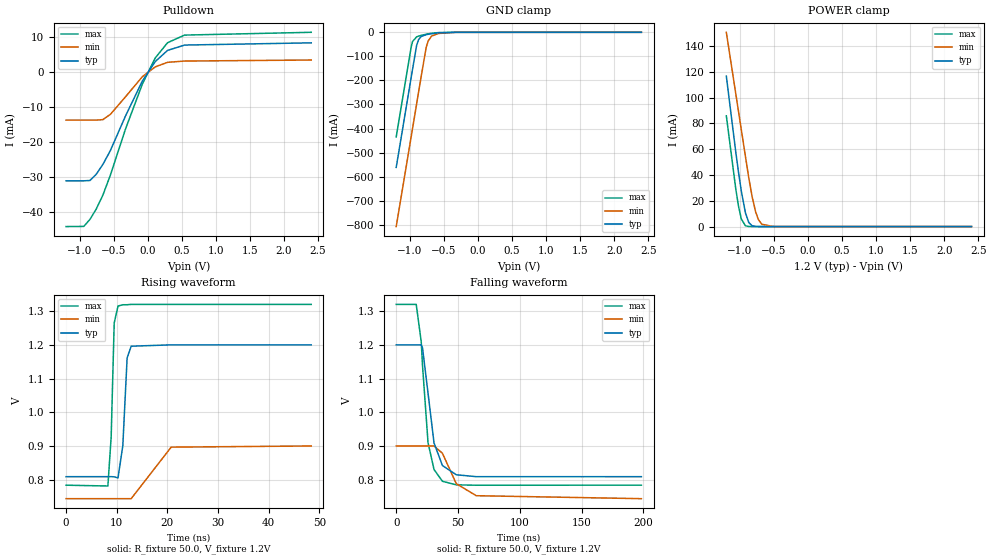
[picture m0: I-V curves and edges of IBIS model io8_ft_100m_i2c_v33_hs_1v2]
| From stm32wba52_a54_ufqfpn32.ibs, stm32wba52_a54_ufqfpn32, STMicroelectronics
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[Model]   io8_ft_100m_i2c_v33_hs_1v2
Model_type I/O_open_drain
Polarity   Non-Inverting
Enable   Active-Low
| CAP_THRESHOLD on pad IOFT is "UDTCAPC" :
| Rising=30.0% of vddiom   Falling=70.0% of vddiom
| C_comp min and max val. don't necessarily correlate with the min and max pvt
| but are the smallest and greatest pad capacitance found.
| var   typ   min   max
C_comp   1.75955pF  1.58205pF  1.89750pF
|C_comp_pulldown   1.75955pF  1.58205pF  1.89750pF
Vinl = 450.0mV
Vinh = 660.0mV
Vmeas = 600.0mV   | Reference voltage for timing measurements
Cref  = 50.0pF   | Timing specification test load capacitance value
Rref  = 1.0MOhm   | Timing specification test load resistance value
Vref  = 660.0mV   | Timing specification test load voltage
[Model Spec]
| TIME_THRESHOLD on pin ZII2CV11 is "CMOS" :
| Rising=50.0% of vdd   Falling=50.0% of vdd
Vinl 436.50000mV 342.50000mV 466.50000mV
Vinh 753.50000mV 549.50000mV 839.50000mV
| variable   typ   min   max
[Temperature Range] 25.0 140.0 -40.0
| variable   typ   min   max
[Voltage Range] 1.2V 900.0mV 1.32V
| variable   typ   min   max
[POWER Clamp Reference] 1.2V 900.0mV 1.32V
| variable   typ   min   max
[GND Clamp Reference] 0V 0V 0V
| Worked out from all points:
|   slope of the pulldown table from 0 to 0.18 V, typ, clamps not added: 40.6 ohm
|   GND clamp passes 1 mA (typ) near -0.51 V on its own axis
|   POWER clamp passes 1 mA (typ) near -0.83 V on its own axis
|   rising waveform, R_fixture 50.0, V_fixture 1.2V: 20-80 % time 747ps typ, 1.42ns min, 564ps max; typ from 0.809 V to 1.2 V
|   falling waveform, R_fixture 50.0, V_fixture 1.2V: 20-80 % time 8.05ns typ, 13.6ns min, 6.4ns max; typ from 1.2 V to 0.809 V
[POWER Clamp]
-1.2V     116.7mA    150.7mA    85.92mA
-1.06V    57.23mA    102.6mA    28.68mA
-1.02V    41.75mA    88.91mA    15.5mA
-980mV    27.6mA     75.18mA    5.935mA
-920mV    10.75mA    54.6mA     597.6uA
-870mV    3.065mA    37.68mA    60.82uA
-820mV    594.6uA    22.85mA    5.912uA
-770mV    99.71uA    11.47mA    572nA
-730mV    23.34uA    5.552mA    88.29nA
-680mV    3.779uA    1.833mA    8.565nA
-510mV    7.889nA    23.13uA    53.67pA
2.4V      0A         0A         0A
[GND Clamp]
-1.2V     -561.6mA   -807.5mA   -434.8mA
-980mV    -187.6mA   -433.5mA   -60.76mA
-960mV    -153.6mA   -399.5mA   -38.21mA
-900mV    -54.17mA   -297.5mA   -18.87mA
-870mV    -29.55mA   -246.5mA   -15.73mA
-830mV    -17.05mA   -178.5mA   -12.57mA
-760mV    -9.921mA   -62.77mA   -8.045mA
-730mV    -8.191mA   -35.56mA   -6.403mA
-680mV    -5.826mA   -15.57mA   -4.089mA
-580mV    -2.43mA    -5.043mA   -1.157mA
-330mV    -11.72uA   -245.5uA   -300.5nA
2.4V      872pA      1.056uA    338.3pA
| variable   typ   min   max
[Pullup Reference] 1.2V 900.0mV 1.32V
| variable   typ   min   max
[Pulldown Reference] 0V 0V 0V
[Pulldown]
-1.2V     -31.2mA    -13.81mA   -44.3mA
-940mV    -31.2mA    -13.81mA   -44.26mA
-850mV    -31.11mA   -13.81mA   -42.26mA
-760mV    -29.39mA   -13.81mA   -39.38mA
-660mV    -26.52mA   -13.68mA   -35.32mA
-550mV    -22.55mA   -12.17mA   -29.6mA
-330mV    -12.74mA   -7.204mA   -16.5mA
-80mV     -2.622mA   -1.37mA    -3.49mA
110mV     2.963mA    1.428mA    3.999mA
290mV     6.144mA    2.737mA    8.347mA
540mV     7.674mA    3.096mA    10.53mA
2.4V      8.312mA    3.39mA     11.33mA
[Ramp]
dV/dt_r 234.64969mV/734.00548ps 93.74534mV/1.39277ns 321.76568mV/559.54409ps
dV/dt_f 234.6588mV/7.92715ns 93.76894mV/13.216ns 321.7731mV/6.31518ns
R_load = 50.0
| Removed startup time: 0s 0s 0s  .
| Removed end time: 48.4ns.
[Rising Waveform]
R_fixture   = 50.0
V_fixture   = 1.2V
V_fixture_min = 900.0mV
V_fixture_max = 1.32V
0s        808.9mV    743.7mV    783.7mV
8.25ns    808.9mV    743.7mV    781.3mV
8.9ns     809mV      743.7mV    926.4mV
9.5ns     808.5mV    743.7mV    1.265V
10.25ns   805.2mV    743.7mV    1.315V
11.2ns    900.8mV    743.7mV    1.319V
12.05ns   1.161V     743.7mV    1.319V
12.85ns   1.196V     743.7mV    1.32V
20.75ns   1.2V       896.6mV    1.32V
48.4ns    1.2V       900mV      1.32V
| Removed startup time: 0s 0s 0s  .
| Removed end time: 198.4ns.
[Falling Waveform]
R_fixture   = 50.0
V_fixture   = 1.2V
V_fixture_min = 900.0mV
V_fixture_max = 1.32V
0s        1.2V       900mV      1.32V
16.2ns    1.2V       900mV      1.32V
20.25ns   1.2V       900mV      1.209V
21.25ns   1.192V     900mV      1.141V
25.75ns   1.057V     900mV      909.8mV
30.6ns    909.1mV    899.9mV    830.3mV
37.4ns    842mV      878.4mV    795.3mV
48.6ns    814.6mV    788.2mV    784.7mV
64.8ns    809mV      752.5mV    783.6mV
198.4ns   808.9mV    743.7mV    783.7mV
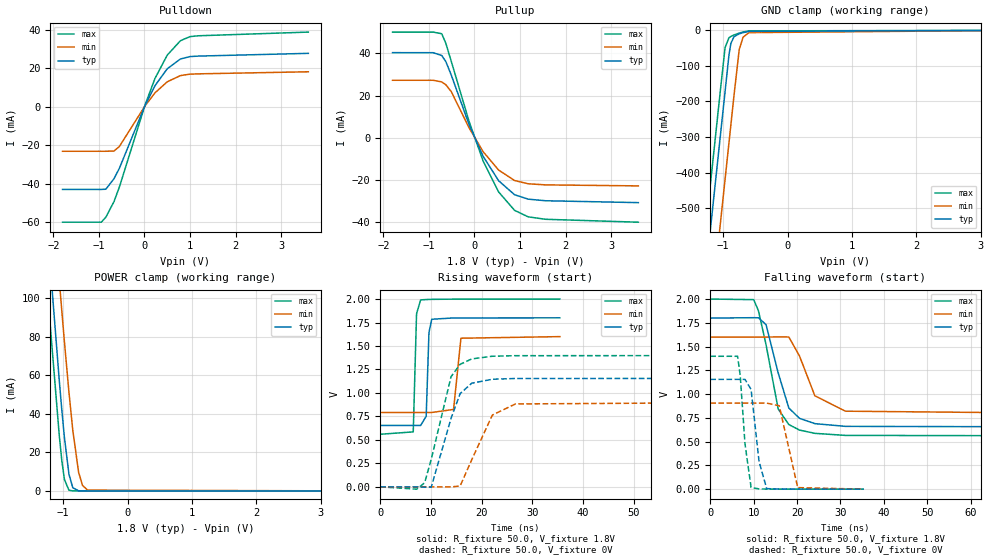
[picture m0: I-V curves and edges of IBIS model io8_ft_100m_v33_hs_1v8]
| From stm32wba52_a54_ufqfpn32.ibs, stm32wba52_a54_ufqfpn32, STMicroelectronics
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[Model]   io8_ft_100m_v33_hs_1v8
Model_type I/O
Polarity   Non-Inverting
Enable   Active-Low
| CAP_THRESHOLD on pad IOFT is "UDTCAPC" :
| Rising=30.0% of vddiom   Falling=70.0% of vddiom
| C_comp min and max val. don't necessarily correlate with the min and max pvt
| but are the smallest and greatest pad capacitance found.
| var   typ   min   max
C_comp   2.30358pF  2.19153pF  2.50001pF
|C_comp_pullup   1.45425pF  1.38855pF  1.55670pF
|C_comp_pulldown   849.33020fF  802.97502fF  943.30706fF
Vinl = 800.0mV
Vinh = 1.0V
Vmeas = 900.0mV   | Reference voltage for timing measurements
Cref  = 50.0pF   | Timing specification test load capacitance value
Rref  = 1.0MOhm   | Timing specification test load resistance value
Vref  = 990.0mV   | Timing specification test load voltage
[Model Spec]
| TIME_THRESHOLD on pin ZIV33M is "CMOS" :
| Rising=50.0% of vddiom   Falling=50.0% of vddiom
Vinl 697.50000mV 636.50000mV 765.50000mV
Vinh 1.08850V 942.50000mV 1.21750V
| variable   typ   min   max
[Temperature Range] 25.0 140.0 -40.0
| variable   typ   min   max
[Voltage Range] 1.8V 1.6V 2.0V
| variable   typ   min   max
[POWER Clamp Reference] 1.8V 1.6V 2.0V
| variable   typ   min   max
[GND Clamp Reference] 0V 0V 0V
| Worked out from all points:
|   slope of the pulldown table from 0 to 0.27 V, typ, clamps not added: 21.7 ohm
|   slope of the pullup table from 0 to 0.27 V, typ, clamps not added: 22.5 ohm
|   GND clamp passes 1 mA (typ) near -0.51 V on its own axis
|   POWER clamp passes 1 mA (typ) near -0.83 V on its own axis
|   rising waveform, R_fixture 50.0, V_fixture 1.8V: 20-80 % time 335ps typ, 529ps min, 257ps max; typ from 0.654 V to 1.8 V
|   falling waveform, R_fixture 50.0, V_fixture 1.8V: 20-80 % time 3.81ns typ, 4.35ns min, 3.59ns max; typ from 1.8 V to 0.654 V
|   rising waveform, R_fixture 50.0, V_fixture 0V: 20-80 % time 3.41ns typ, 4.28ns min, 3.58ns max; typ from 0 V to 1.16 V
|   falling waveform, R_fixture 50.0, V_fixture 0V: 20-80 % time 1.72ns typ, 2.14ns min, 1.41ns max; typ from 1.16 V to 0 V
[POWER Clamp]
-1.8V     396.4mA    438.1mA    365.5mA
-1.26V    143.5mA    194.6mA    112.6mA
-1.19V    112.3mA    164.2mA    81.56mA
-1.06V    57.23mA    109.3mA    28.68mA
-1.02V    41.75mA    93.06mA    15.5mA
-980mV    27.6mA     77.28mA    5.935mA
-910mV    8.693mA    51.24mA    382.3uA
-850mV    1.642mA    31.41mA    23.97uA
-760mV    69.41uA    9.714mA    358.6nA
-700mV    7.83uA     2.919mA    21.79nA
-620mV    424.6nA    410.3uA    573.9pA
3.6V      0A         0A         0A
[GND Clamp]
-1.8V     -1.583A    -1.83A     -1.456A
-1.43V    -953.9mA   -1.201A    -826.8mA
-1.24V    -630.9mA   -877.8mA   -503.8mA
-1.05V    -307.9mA   -554.8mA   -180.8mA
-970mV    -171.9mA   -418.8mA   -48.31mA
-910mV    -69.87mA   -316.8mA   -20.91mA
-880mV    -36.5mA    -265.8mA   -17.19mA
-830mV    -17.68mA   -180.8mA   -12.97mA
-750mV    -9.66mA    -53.66mA   -7.697mA
-690mV    -6.479mA   -19.19mA   -4.622mA
-600mV    -3.058mA   -6.478mA   -1.59mA
3.6V      1.279nA    1.39uA     517.2pA
| variable   typ   min   max
[Pullup Reference] 1.8V 1.6V 2.0V
| variable   typ   min   max
[Pulldown Reference] 0V 0V 0V
[Pullup]
-1.8V     40.39mA    27.3mA     50.15mA
-910mV    40.38mA    27.3mA     50.15mA
-720mV    39.05mA    26.52mA    49.37mA
-630mV    36.18mA    25.18mA    44.85mA
-510mV    29.75mA    21.91mA    36.26mA
-120mV    6.338mA    4.782mA    7.854mA
190mV     -8.788mA   -6.58mA    -11.01mA
530mV     -20.35mA   -15.28mA   -25.66mA
880mV     -26.99mA   -20.26mA   -34.39mA
1.18V     -29.09mA   -21.8mA    -37.49mA
1.56V     -29.85mA   -22.32mA   -38.64mA
3.6V      -30.74mA   -22.8mA    -40.02mA
[Pulldown]
-1.8V     -42.97mA   -23.15mA   -59.99mA
-950mV    -42.97mA   -23.15mA   -59.99mA
-850mV    -42.87mA   -23.15mA   -57.45mA
-670mV    -37.41mA   -23.03mA   -49.3mA
-550mV    -31.91mA   -20.61mA   -41.6mA
10mV      539.8uA    356.7uA    722uA
230mV     10.88mA    7.174mA    14.64mA
500mV     19.69mA    12.93mA    26.79mA
790mV     24.78mA    16.15mA    34.26mA
1V        26.02mA    16.89mA    36.38mA
1.18V     26.27mA    17.05mA    36.82mA
3.6V      27.7mA     18.13mA    38.74mA
[Ramp]
dV/dt_r 693.10493mV/3.39583ns 543.25561mV/4.21778ns 838.83761mV/3.57972ns
dV/dt_f 687.6932mV/3.74802ns 484.94014mV/4.33932ns 864.00316mV/3.58208ns
R_load = 50.0
| Removed startup time: 0s 0s 0s  .
| Removed end time: 35.4ns.
[Rising Waveform]
R_fixture   = 50.0
V_fixture   = 1.8V
V_fixture_min = 1.6V
V_fixture_max = 2.0V
0s        653.8mV    791.8mV    560mV
6.5ns     653.8mV    791.8mV    585.5mV
7.15ns    653.9mV    791.8mV    1.843V
7.95ns    653.7mV    791.8mV    1.991V
9.05ns    751.5mV    791.8mV    1.995V
9.6ns     1.645V     791.8mV    1.996V
10.15ns   1.785V     791.8mV    1.997V
14.45ns   1.799V     824.5mV    1.999V
15.9ns    1.799V     1.583V     2V
35.4ns    1.8V       1.6V       2V
| Removed startup time: 0s 0s 0s  .
| Removed end time: 98.4ns.
[Falling Waveform]
R_fixture   = 50.0
V_fixture   = 1.8V
V_fixture_min = 1.6V
V_fixture_max = 2.0V
0s        1.8V       1.6V       2V
10ns      1.804V     1.6V       1.994V
11.1ns    1.803V     1.6V       1.877V
12.85ns   1.731V     1.6V       1.52V
15.65ns   1.223V     1.602V     843.3mV
18.1ns    854.1mV    1.601V     679.9mV
20.55ns   745.4mV    1.402V     622mV
24.1ns    689.4mV    982.3mV    587.3mV
31.15ns   660.7mV    820.4mV    565.7mV
98.4ns    653.8mV    791.8mV    560mV
| Removed startup time: 0s 0s 0s  .
| Removed end time: 98.35ns.
[Rising Waveform]
R_fixture   = 50.0
V_fixture   = 0V
V_fixture_min = 0V
V_fixture_max = 0V
0s        4.767nV    680.3nV    4.104nV
7.2ns     1.252uV    679.1nV    -24.73mV
8.75ns    -3.712mV   677.3nV    44.19mV
10.05ns   -3.566mV   718.1nV    293.7mV
13.95ns   729.5mV    -1.199mV   1.173V
15.75ns   993.5mV    9.721mV    1.305V
18.05ns   1.104V     291mV      1.363V
22.1ns    1.146V     764.9mV    1.391V
26.65ns   1.154V     883mV      1.397V
98.35ns   1.155V     905.4mV    1.398V
| Removed startup time: 0s 0s 0s  .
| Removed end time: 35.4ns.
[Falling Waveform]
R_fixture   = 50.0
V_fixture   = 0V
V_fixture_min = 0V
V_fixture_max = 0V
0s        1.155V     905.5mV    1.398V
6.3ns     1.155V     905.5mV    1.398V
6.9ns     1.155V     905.5mV    1.196V
8ns       1.155V     905.5mV    477.8mV
9.4ns     1.05V      905.5mV    18.43mV
11.25ns   288.3mV    905.5mV    2.637mV
13ns      5.729mV    905.5mV    1.028mV
15.9ns    1.01mV     877mV      500.8uV
20.15ns   327.9uV    16.35mV    204.5uV
35.4ns    8.379uV    89.12uV    6.9uV
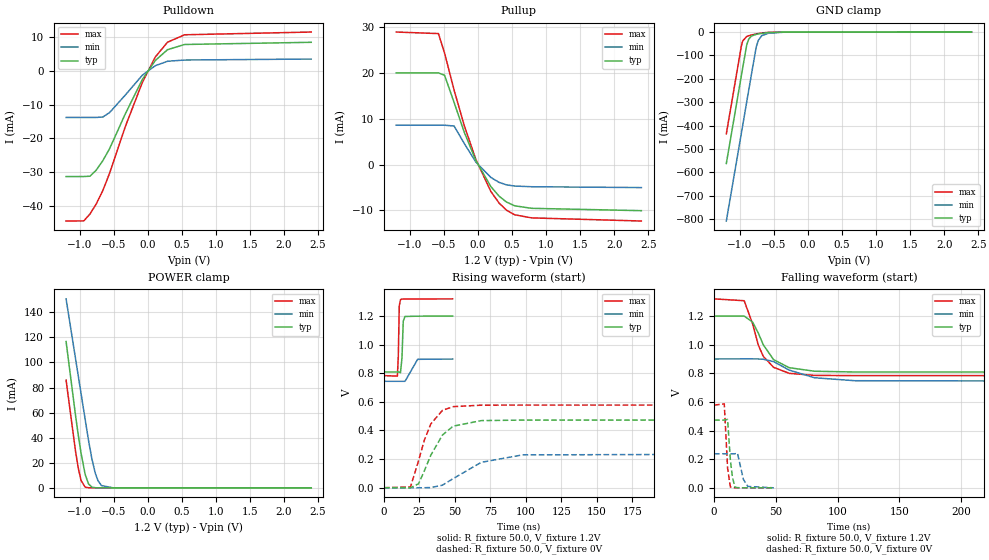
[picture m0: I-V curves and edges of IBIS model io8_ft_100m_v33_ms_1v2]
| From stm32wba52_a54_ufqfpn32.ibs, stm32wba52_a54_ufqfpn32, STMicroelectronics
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[Model]   io8_ft_100m_v33_ms_1v2
Model_type I/O
Polarity   Non-Inverting
Enable   Active-Low
| CAP_THRESHOLD on pad IOFT is "UDTCAPC" :
| Rising=30.0% of vddiom   Falling=70.0% of vddiom
| C_comp min and max val. don't necessarily correlate with the min and max pvt
| but are the smallest and greatest pad capacitance found.
| var   typ   min   max
C_comp   1.83453pF  1.64923pF  1.97632pF
|C_comp_pullup   1.12505pF  1.02587pF  1.16105pF
|C_comp_pulldown   709.48000fF  623.35501fF  815.26500fF
Vinl = 450.0mV
Vinh = 660.0mV
Vmeas = 600.0mV   | Reference voltage for timing measurements
Cref  = 50.0pF   | Timing specification test load capacitance value
Rref  = 1.0MOhm   | Timing specification test load resistance value
Vref  = 660.0mV   | Timing specification test load voltage
[Model Spec]
| TIME_THRESHOLD on pin ZIV33M is "CMOS" :
| Rising=50.0% of vddiom   Falling=50.0% of vddiom
Vinl 436.50000mV 342.50000mV 466.50000mV
Vinh 753.50000mV 549.50000mV 839.50000mV
| variable   typ   min   max
[Temperature Range] 25.0 140.0 -40.0
| variable   typ   min   max
[Voltage Range] 1.2V 900.0mV 1.32V
| variable   typ   min   max
[POWER Clamp Reference] 1.2V 900.0mV 1.32V
| variable   typ   min   max
[GND Clamp Reference] 0V 0V 0V
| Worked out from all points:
|   slope of the pulldown table from 0 to 0.18 V, typ, clamps not added: 40.6 ohm
|   slope of the pullup table from 0 to 0.18 V, typ, clamps not added: 39.4 ohm
|   GND clamp passes 1 mA (typ) near -0.51 V on its own axis
|   POWER clamp passes 1 mA (typ) near -0.83 V on its own axis
|   rising waveform, R_fixture 50.0, V_fixture 1.2V: 20-80 % time 847ps typ, 1.6ns min, 596ps max; typ from 0.809 V to 1.2 V
|   falling waveform, R_fixture 50.0, V_fixture 1.2V: 20-80 % time 15.9ns typ, 26.5ns min, 13.8ns max; typ from 1.2 V to 0.809 V
|   rising waveform, R_fixture 50.0, V_fixture 0V: 20-80 % time 14.7ns typ, 26ns min, 11.5ns max; typ from 0 V to 0.473 V
|   falling waveform, R_fixture 50.0, V_fixture 0V: 20-80 % time 2.69ns typ, 4.08ns min, 2.22ns max; typ from 0.473 V to 0 V
[POWER Clamp]
-1.2V     116.7mA    150.7mA    85.92mA
-1.06V    57.23mA    102.6mA    28.68mA
-1.02V    41.75mA    88.91mA    15.5mA
-980mV    27.6mA     75.18mA    5.935mA
-920mV    10.75mA    54.6mA     597.6uA
-870mV    3.065mA    37.68mA    60.82uA
-820mV    594.6uA    22.85mA    5.912uA
-770mV    99.71uA    11.47mA    572nA
-730mV    23.34uA    5.552mA    88.29nA
-680mV    3.779uA    1.833mA    8.565nA
-510mV    7.889nA    23.13uA    53.67pA
2.4V      0A         0A         0A
[GND Clamp]
-1.2V     -561.6mA   -807.5mA   -434.8mA
-980mV    -187.6mA   -433.5mA   -60.76mA
-960mV    -153.6mA   -399.5mA   -38.21mA
-900mV    -54.17mA   -297.5mA   -18.87mA
-870mV    -29.55mA   -246.5mA   -15.73mA
-830mV    -17.05mA   -178.5mA   -12.57mA
-760mV    -9.921mA   -62.77mA   -8.045mA
-730mV    -8.191mA   -35.56mA   -6.403mA
-680mV    -5.826mA   -15.57mA   -4.089mA
-580mV    -2.43mA    -5.043mA   -1.157mA
-330mV    -11.72uA   -245.5uA   -300.5nA
2.4V      872pA      1.055uA    338.3pA
| variable   typ   min   max
[Pullup Reference] 1.2V 900.0mV 1.32V
| variable   typ   min   max
[Pulldown Reference] 0V 0V 0V
[Pullup]
-1.2V     20.06mA    8.63mA     28.99mA
-580mV    20.06mA    8.63mA     28.65mA
-490mV    19.55mA    8.63mA     24.4mA
-350mV    13.61mA    8.456mA    16.3mA
-200mV    7.069mA    4.622mA    8.528mA
-30mV     926.7uA    571.2uA    1.132mA
190mV     -4.777mA   -2.782mA   -5.837mA
310mV     -6.857mA   -3.851mA   -8.366mA
420mV     -8.158mA   -4.403mA   -9.943mA
540mV     -8.979mA   -4.661mA   -10.94mA
790mV     -9.528mA   -4.812mA   -11.62mA
2.4V      -10.04mA   -4.994mA   -12.3mA
[Pulldown]
-1.2V     -31.2mA    -13.81mA   -44.3mA
-940mV    -31.2mA    -13.81mA   -44.26mA
-850mV    -31.11mA   -13.81mA   -42.26mA
-760mV    -29.39mA   -13.81mA   -39.38mA
-660mV    -26.52mA   -13.68mA   -35.32mA
-560mV    -22.95mA   -12.35mA   -30.17mA
-330mV    -12.74mA   -7.204mA   -16.5mA
-80mV     -2.622mA   -1.37mA    -3.49mA
110mV     2.963mA    1.428mA    3.999mA
290mV     6.144mA    2.737mA    8.347mA
540mV     7.674mA    3.096mA    10.53mA
2.4V      8.319mA    3.393mA    11.34mA
[Ramp]
dV/dt_r 283.7947mV/14.63352ns 142.77292mV/25.73792ns 346.61938mV/11.4441ns
dV/dt_f 234.6598mV/15.76776ns 93.76396mV/25.5519ns 321.77307mV/12.76626ns
R_load = 50.0
| Removed startup time: 0s 0s 0s  .
| Removed end time: 48.4ns.
[Rising Waveform]
R_fixture   = 50.0
V_fixture   = 1.2V
V_fixture_min = 900.0mV
V_fixture_max = 1.32V
0s        808.9mV    743.7mV    783.7mV
9.45ns    808.9mV    743.7mV    779.9mV
10.1ns    809mV      743.7mV    912.9mV
10.8ns    808.4mV    743.7mV    1.272V
11.65ns   804.3mV    743.7mV    1.315V
12.7ns    907.2mV    743.7mV    1.318V
13.6ns    1.165V     743.7mV    1.319V
14.85ns   1.197V     743.7mV    1.319V
23.75ns   1.199V     897.5mV    1.319V
48.4ns    1.2V       899.6mV    1.32V
| Removed startup time: 0s 0s 0s  .
| Removed end time: 398.4ns.
[Falling Waveform]
R_fixture   = 50.0
V_fixture   = 1.2V
V_fixture_min = 900.0mV
V_fixture_max = 1.32V
0s        1.2V       900mV      1.32V
24.4ns    1.2V       900.8mV    1.307V
31.3ns    1.157V     900.7mV    1.143V
35.8ns    1.081V     900.2mV    997.6mV
39.85ns   999.3mV    898.3mV    918.5mV
48.2ns    895.3mV    881.9mV    841.8mV
60.9ns    839.3mV    822.3mV    799.7mV
81.3ns    814.5mV    769.1mV    785.6mV
113.9ns   809.2mV    748.4mV    783.7mV
398.4ns   808.9mV    743.7mV    783.7mV
| Removed startup time: 0s 0s 0s  .
| Removed end time: 398.4ns.
[Rising Waveform]
R_fixture   = 50.0
V_fixture   = 0V
V_fixture_min = 0V
V_fixture_max = 0V
0s        4.84nV     985.4nV    4.251nV
18.7ns    -302.2uV   30.37uV    5.538mV
24.4ns    27.84mV    -898.1uV   189.1mV
28.35ns   115.3mV    7.408uV    329mV
33ns      226.8mV    1.222mV    446mV
41.25ns   368.7mV    17.95mV    540.9mV
48.8ns    430.3mV    64.12mV    566.6mV
68.6ns    469.1mV    177.7mV    577mV
97.6ns    472.7mV    229.4mV    577.6mV
398.4ns   473mV      238mV      577.7mV
| Removed startup time: 0s 0s 0s  .
| Removed end time: 48.4ns.
[Falling Waveform]
R_fixture   = 50.0
V_fixture   = 0V
V_fixture_min = 0V
V_fixture_max = 0V
0s        473mV      238mV      577.7mV
8.25ns    473mV      238mV      586.7mV
10.95ns   477.9mV    238mV      137.6mV
13.2ns    194.9mV    238mV      6.133mV
14.85ns   74.92mV    238mV      1.902mV
16.95ns   4.125mV    238mV      882uV
18.95ns   1.348mV    242.4mV    568.8uV
23.7ns    498.8uV    60.28mV    631uV
27.3ns    369.4uV    9.997mV    474.3uV
48.4ns    91.1uV     206.2uV    46.43uV
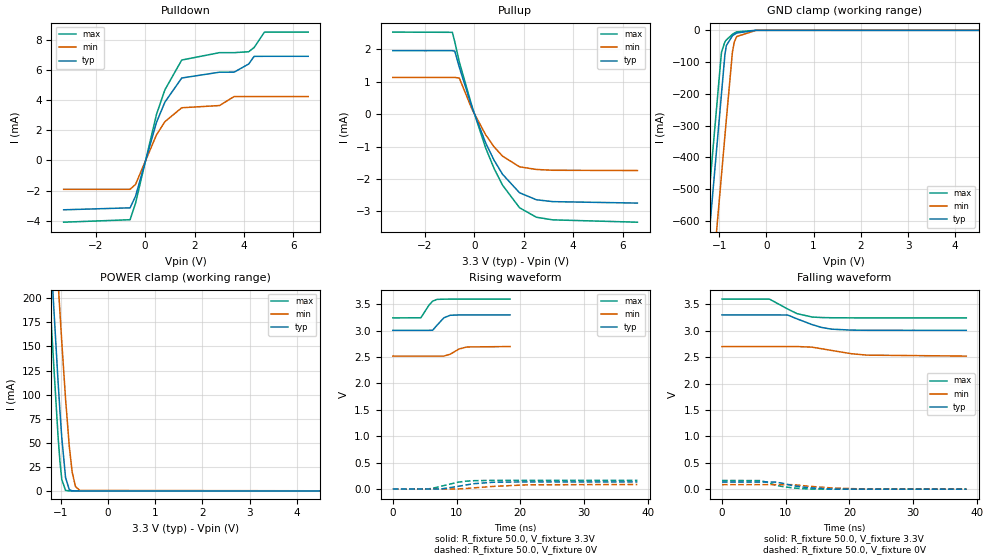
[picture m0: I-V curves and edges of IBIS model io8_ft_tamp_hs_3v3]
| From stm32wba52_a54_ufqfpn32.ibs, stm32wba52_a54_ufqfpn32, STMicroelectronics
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[Model]   io8_ft_tamp_hs_3v3
Model_type I/O
Polarity   Non-Inverting
Enable   Active-Low
| CAP_THRESHOLD on pad IOFT is "UDTCAPC" :
| Rising=30.0% of vddiom   Falling=70.0% of vddiom
| C_comp min and max val. don't necessarily correlate with the min and max pvt
| but are the smallest and greatest pad capacitance found.
| var   typ   min   max
C_comp   8.02922pF  7.67207pF  8.31249pF
|C_comp_pullup   5.44741pF  5.17628pF  5.56539pF
|C_comp_pulldown   2.58181pF  2.49579pF  2.74710pF
Vinl = 1.35V
Vinh = 1.8V
Vmeas = 1.65V   | Reference voltage for timing measurements
Cref  = 50.0pF   | Timing specification test load capacitance value
Rref  = 1.0MOhm   | Timing specification test load resistance value
Vref  = 1.815V   | Timing specification test load voltage
[Model Spec]
| TIME_THRESHOLD on pin ZIV33SW is "CMOS" :
| Rising=50.0% of VDDV33SW   Falling=50.0% of VDDV33SW
Vinl 1.28450V 1.07650V 1.38450V
Vinh 1.79550V 1.49050V 1.94250V
| variable   typ   min   max
[Temperature Range] 25.0 140.0 -40.0
| variable   typ   min   max
[Voltage Range] 3.3V 2.7V 3.6V
| variable   typ   min   max
[POWER Clamp Reference] 3.3V 2.7V 3.6V
| variable   typ   min   max
[GND Clamp Reference] 0V 0V 0V
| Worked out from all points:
|   slope of the pulldown table from 0 to 0.495 V, typ, clamps not added: 186 ohm
|   slope of the pullup table from 0 to 0.495 V, typ, clamps not added: 523 ohm
|   GND clamp passes 1 mA (typ) near -0.47 V on its own axis
|   POWER clamp passes 1 mA (typ) near -0.81 V on its own axis
|   rising waveform, R_fixture 50.0, V_fixture 3.3V: 20-80 % time 1.26ns typ, 1.6ns min, 1.13ns max; typ from 3.01 V to 3.3 V
|   falling waveform, R_fixture 50.0, V_fixture 3.3V: 20-80 % time 4.11ns typ, 5.59ns min, 3.54ns max; typ from 3.3 V to 3.01 V
|   rising waveform, R_fixture 50.0, V_fixture 0V: 20-80 % time 4.08ns typ, 5.97ns min, 3.4ns max; typ from 0 V to 0.135 V
|   falling waveform, R_fixture 50.0, V_fixture 0V: 20-80 % time 4ns typ, 5.63ns min, 3.43ns max; typ from 0.135 V to 0 V
[POWER Clamp]
-3.3V     2.246A     2.279A     2.182A
-1.26V    287mA      389.3mA    225.1mA
-1.19V    224.6mA    328.4mA    163.1mA
-1.06V    114.5mA    218.6mA    57.35mA
-1.02V    83.5mA     186.1mA    30.99mA
-980mV    55.21mA    154.6mA    11.87mA
-900mV    13.79mA    95.47mA    485.6uA
-820mV    1.189mA    45.7mA     11.82uA
-760mV    138.8uA    19.43mA    717.3nA
-690mV    10.88uA    4.64mA     27.56nA
-600mV    410.2nA    489.5uA    725pA
6.6V      0A         0A         0A
[GND Clamp]
-3.3V     -4.191A    -4.447A    -4.059A
-1.59V    -1.284A    -1.54A     -1.152A
-1.25V    -705.7mA   -962.2mA   -574mA
-960mV    -212.7mA   -469.2mA   -81mA
-950mV    -195.7mA   -452.2mA   -68.07mA
-880mV    -77.2mA    -333.2mA   -36.04mA
-850mV    -48.09mA   -282.2mA   -30.39mA
-720mV    -17.06mA   -67.51mA   -12.51mA
-680mV    -12.85mA   -36.48mA   -8.6mA
-630mV    -8.529mA   -19.6mA    -4.86mA
-220mV    -490.4nA   -42.83uA   -18.74nA
6.6V      5.835nA    6.044uA    3.958nA
| variable   typ   min   max
[Pullup Reference] 3.3V 2.7V 3.6V
| variable   typ   min   max
[Pulldown Reference] 0V 0V 0V
[Pullup]
-3.3V     1.956mA    1.132mA    2.53mA
-890mV    1.956mA    1.132mA    2.523mA
-790mV    1.939mA    1.132mA    2.221mA
-610mV    1.448mA    1.114mA    1.613mA
-90mV     195.3uA    143.2uA    228.7uA
460mV     -891.2uA   -639.5uA   -1.049mA
800mV     -1.423mA   -1.009mA   -1.677mA
1.14V     -1.853mA   -1.295mA   -2.188mA
1.83V     -2.424mA   -1.624mA   -2.886mA
2.51V     -2.639mA   -1.705mA   -3.178mA
3.17V     -2.697mA   -1.73mA    -3.259mA
6.6V      -2.742mA   -1.738mA   -3.331mA
[Pulldown]
-3.3V     -3.274mA   -1.917mA   -4.095mA
-610mV    -3.144mA   -1.917mA   -3.932mA
-390mV    -2.378mA   -1.591mA   -2.836mA
460mV     2.524mA    1.696mA    3.053mA
800mV     3.862mA    2.563mA    4.678mA
1.48V     5.456mA    3.486mA    6.647mA
3.01V     5.842mA    3.632mA    7.136mA
3.6V      5.844mA    4.228mA    7.136mA
4.19V     6.383mA    4.228mA    7.196mA
4.41V     6.889mA    4.228mA    7.475mA
4.83V     6.894mA    4.228mA    8.498mA
6.6V      6.894mA    4.228mA    8.498mA
[Ramp]
dV/dt_r 80.90418mV/4.07243ns 51.29585mV/5.95048ns 98.35024mV/3.38934ns
dV/dt_f 175.29607mV/4.09952ns 108.27675mV/5.58062ns 214.11319mV/3.52754ns
R_load = 50.0
| Removed startup time: 0s 0s 0s  .
| Removed end time: 18.4ns.
[Rising Waveform]
R_fixture   = 50.0
V_fixture   = 3.3V
V_fixture_min = 2.7V
V_fixture_max = 3.6V
0s        3.008V     2.519V     3.243V
4.4ns     3.008V     2.519V     3.245V
5.65ns    3.008V     2.519V     3.48V
6.25ns    3.009V     2.519V     3.561V
6.95ns    3.105V     2.519V     3.594V
8ns       3.243V     2.519V     3.598V
9ns       3.293V     2.554V     3.599V
10.4ns    3.299V     2.654V     3.6V
11.65ns   3.3V       2.692V     3.6V
18.4ns    3.3V       2.7V       3.6V
| Removed startup time: 0s 0s 0s  .
| Removed end time: 38.35ns.
[Falling Waveform]
R_fixture   = 50.0
V_fixture   = 3.3V
V_fixture_min = 2.7V
V_fixture_max = 3.6V
0s        3.3V       2.7V       3.6V
7.45ns    3.3V       2.7V       3.599V
10.3ns    3.298V     2.7V       3.412V
11.8ns    3.224V     2.701V     3.323V
14.15ns   3.116V     2.689V     3.26V
15.65ns   3.062V     2.659V     3.25V
17.2ns    3.03V      2.627V     3.246V
20.3ns    3.012V     2.565V     3.244V
22.75ns   3.009V     2.538V     3.243V
38.35ns   3.008V     2.52V      3.243V
| Removed startup time: 0s 0s 0s  .
| Removed end time: 38.4ns.
[Rising Waveform]
R_fixture   = 50.0
V_fixture   = 0V
V_fixture_min = 0V
V_fixture_max = 0V
0s        162.8nV    4.5uV      290.6nV
5.3ns     1.622uV    4.5uV      -3.14mV
6.3ns     -1.174mV   4.653uV    15.2mV
7.55ns    323.3uV    9.53uV     51.62mV
10.2ns    49.43mV    736.9uV    128.7mV
11.5ns    77.13mV    10.18mV    148.4mV
12.8ns    101.8mV    21.93mV    157.5mV
15.85ns   128.5mV    50.06mV    163.2mV
21.2ns    134.6mV    79.64mV    163.9mV
38.4ns    134.8mV    85.5mV     163.9mV
| Removed startup time: 0s 0s 0s  .
| Removed end time: 38.4ns.
[Falling Waveform]
R_fixture   = 50.0
V_fixture   = 0V
V_fixture_min = 0V
V_fixture_max = 0V
0s        134.9mV    85.5mV     163.9mV
5.9ns     134.9mV    85.5mV     162.7mV
6.9ns     134.9mV    85.5mV     137mV
8.35ns    134.3mV    85.5mV     77.77mV
9.4ns     114.4mV    85.5mV     51.36mV
11.25ns   62.49mV    84.49mV    22.15mV
13.5ns    28.5mV     56.6mV     3.319mV
17.25ns   2.64mV     22.73mV    159.2uV
21.95ns   101.5uV    4.14mV     17.12uV
38.4ns    271.8nV    7.445uV    314.6nV
